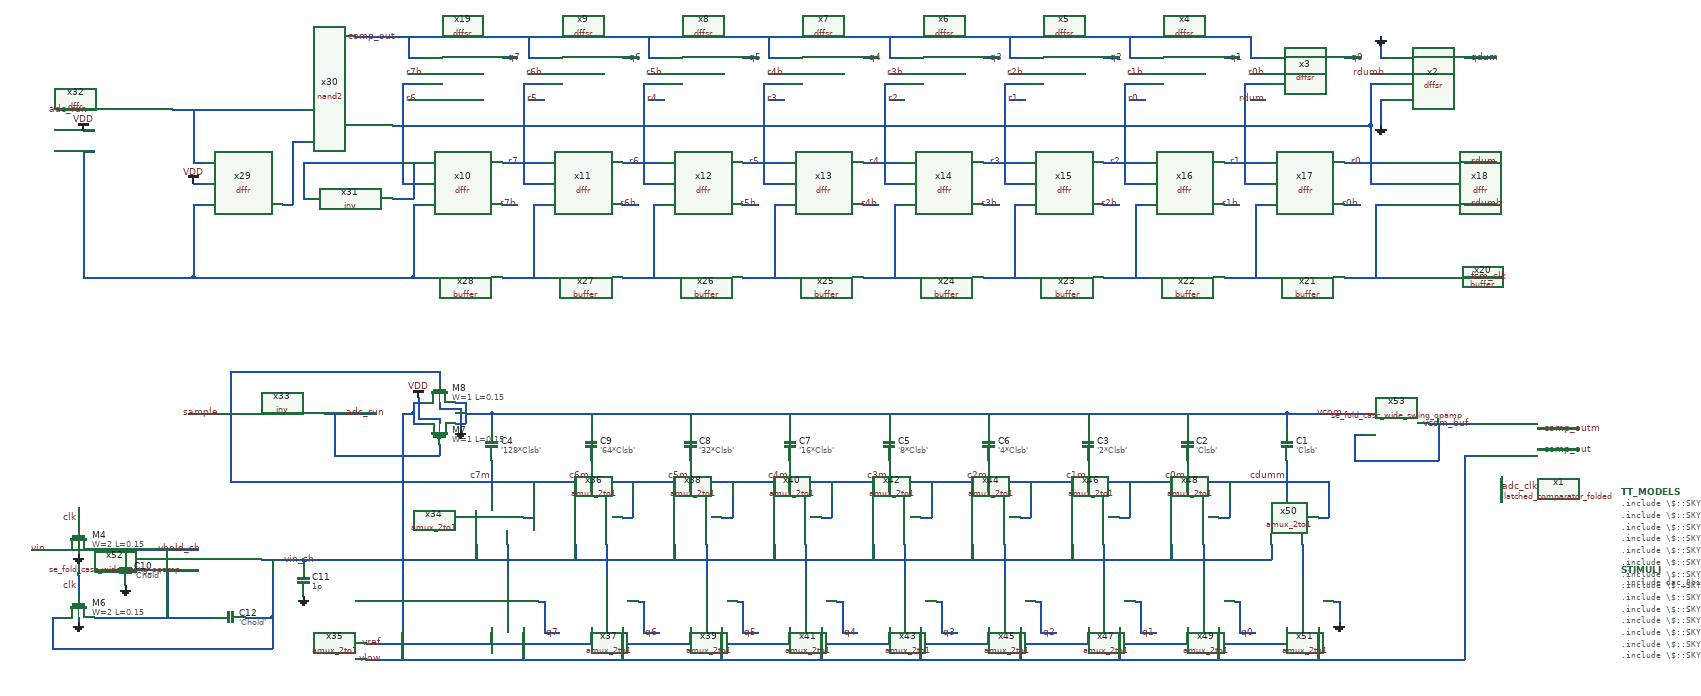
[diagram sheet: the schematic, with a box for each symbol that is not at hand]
v {xschem version=2.9.9 file_version=1.2 }
G {}
K {}
V {}
S {}
E {}
N 280 -1370 310 -1370 { lab=r6}
N 460 -1450 490 -1450 { lab=q7}
N 280 -1450 310 -1450 { lab=comp_out}
N 510 -1370 540 -1370 { lab=r5}
N 690 -1450 720 -1450 { lab=q6}
N 510 -1450 540 -1450 { lab=comp_out}
N 740 -1370 770 -1370 { lab=r4}
N 920 -1450 950 -1450 { lab=q5}
N 740 -1450 770 -1450 { lab=comp_out}
N 970 -1370 1000 -1370 { lab=r3}
N 1150 -1450 1180 -1450 { lab=q4}
N 970 -1450 1000 -1450 { lab=comp_out}
N 1200 -1370 1230 -1370 { lab=r2}
N 1380 -1450 1410 -1450 { lab=q3}
N 1200 -1450 1230 -1450 { lab=comp_out}
N 1430 -1370 1460 -1370 { lab=r1}
N 1610 -1450 1640 -1450 { lab=q2}
N 1430 -1450 1460 -1450 { lab=comp_out}
N 1660 -1370 1690 -1370 { lab=r0}
N 1840 -1450 1870 -1450 { lab=q1}
N 1660 -1450 1690 -1450 { lab=comp_out}
N 1890 -1370 1920 -1370 { lab=rdum}
N 2070 -1450 2100 -1450 { lab=q0}
N 1890 -1450 1920 -1450 { lab=comp_out}
N 180 -1490 1890 -1490 { lab=comp_out}
N 1890 -1490 1890 -1450 { lab=comp_out}
N 1660 -1490 1660 -1450 { lab=comp_out}
N 1430 -1490 1430 -1450 { lab=comp_out}
N 1200 -1490 1200 -1450 { lab=comp_out}
N 970 -1490 970 -1450 { lab=comp_out}
N 740 -1490 740 -1450 { lab=comp_out}
N 510 -1490 510 -1450 { lab=comp_out}
N 280 -1490 280 -1450 { lab=comp_out}
N 460 -1250 540 -1250 { lab=r7}
N 690 -1250 770 -1250 { lab=r6}
N 920 -1250 1000 -1250 { lab=r5}
N 1150 -1250 1230 -1250 { lab=r4}
N 1610 -1250 1690 -1250 { lab=r2}
N 1840 -1250 1920 -1250 { lab=r1}
N 2070 -1250 2150 -1250 { lab=r0}
N 1380 -1250 1460 -1250 { lab=r3}
N 460 -1170 490 -1170 { lab=r7b}
N 690 -1170 720 -1170 { lab=r6b}
N 920 -1170 950 -1170 { lab=r5b}
N 1150 -1170 1180 -1170 { lab=r4b}
N 1380 -1170 1410 -1170 { lab=r3b}
N 1610 -1170 1640 -1170 { lab=r2b}
N 1840 -1170 1870 -1170 { lab=r1b}
N 2070 -1170 2100 -1170 { lab=r0b}
N 280 -1420 310 -1420 { lab=r7b}
N 510 -1420 540 -1420 { lab=r6b}
N 740 -1420 770 -1420 { lab=r5b}
N 970 -1420 1000 -1420 { lab=r4b}
N 1200 -1420 1230 -1420 { lab=r3b}
N 1430 -1420 1460 -1420 { lab=r2b}
N 1660 -1420 1690 -1420 { lab=r1b}
N 1890 -1420 1920 -1420 { lab=r0b}
N 2120 -1420 2150 -1420 { lab=rdumb}
N 460 -1030 550 -1030 { lab=#net1}
N 690 -1030 780 -1030 { lab=#net2}
N 920 -1030 1010 -1030 { lab=#net3}
N 1150 -1030 1240 -1030 { lab=#net4}
N 1380 -1030 1470 -1030 { lab=#net5}
N 1610 -1030 1700 -1030 { lab=#net6}
N 1840 -1030 1930 -1030 { lab=#net7}
N 2070 -1030 2160 -1030 { lab=#net8}
N 2300 -1030 2370 -1030 { lab=fsm_clk}
N 290 -1030 320 -1030 { lab=#net9}
N 290 -1170 290 -1030 { lab=#net9}
N 520 -1170 540 -1170 { lab=#net1}
N 520 -1170 520 -1030 { lab=#net1}
N 750 -1170 770 -1170 { lab=#net2}
N 750 -1170 750 -1030 { lab=#net2}
N 980 -1170 1000 -1170 { lab=#net3}
N 980 -1170 980 -1030 { lab=#net3}
N 1210 -1170 1230 -1170 { lab=#net4}
N 1210 -1170 1210 -1030 { lab=#net4}
N 1440 -1170 1460 -1170 { lab=#net5}
N 1440 -1170 1440 -1030 { lab=#net5}
N 1670 -1170 1690 -1170 { lab=#net6}
N 1670 -1170 1670 -1030 { lab=#net6}
N 1900 -1170 1920 -1170 { lab=#net7}
N 1900 -1170 1900 -1030 { lab=#net7}
N 2130 -1170 2150 -1170 { lab=#net8}
N 2130 -1170 2130 -1030 { lab=#net8}
N 2120 -1400 2120 -1320 { lab=#net10}
N 2120 -1400 2150 -1400 { lab=#net10}
N 1880 -1400 1920 -1400 { lab=#net10}
N 1880 -1400 1880 -1320 { lab=#net10}
N 1650 -1400 1690 -1400 { lab=#net10}
N 1650 -1400 1650 -1320 { lab=#net10}
N 1420 -1400 1460 -1400 { lab=#net10}
N 1420 -1400 1420 -1320 { lab=#net10}
N 1190 -1400 1230 -1400 { lab=#net10}
N 1190 -1400 1190 -1320 { lab=#net10}
N 960 -1400 1000 -1400 { lab=#net10}
N 960 -1400 960 -1320 { lab=#net10}
N 730 -1400 770 -1400 { lab=#net10}
N 730 -1400 730 -1320 { lab=#net10}
N 500 -1400 540 -1400 { lab=#net10}
N 500 -1400 500 -1320 { lab=#net10}
N 270 -1400 310 -1400 { lab=#net10}
N 270 -1400 270 -1320 { lab=#net10}
N 290 -1170 310 -1170 { lab=#net9}
N 2300 -1170 2360 -1170 { lab=rdumb}
N 2300 -1250 2360 -1250 { lab=rdum}
N 2300 -1450 2360 -1450 { lab=qdum}
N 270 -1320 270 -1210 { lab=#net10}
N 270 -1210 310 -1210 { lab=#net10}
N 2140 -1370 2140 -1320 { lab=GND}
N 2140 -1450 2150 -1450 { lab=GND}
N 2140 -1490 2140 -1450 { lab=GND}
N 60 -1290 80 -1290 { lab=#net11}
N -130 -1250 -110 -1250 { lab=#net12}
N -130 -1350 -130 -1250 { lab=#net12}
N 250 -1320 2120 -1320 { lab=#net10}
N 60 -1290 60 -1170 { lab=#net11}
N 40 -1170 60 -1170 { lab=#net11}
N -130 -1030 290 -1030 { lab=#net9}
N -130 -1170 -130 -1030 { lab=#net9}
N -130 -1170 -110 -1170 { lab=#net9}
N 250 -1180 290 -1180 { lab=#net13}
N 290 -1250 290 -1180 { lab=#net13}
N 290 -1250 310 -1250 { lab=#net13}
N 80 -1180 90 -1180 { lab=#net10}
N 80 -1250 80 -1180 { lab=#net10}
N 80 -1250 270 -1250 { lab=#net10}
N -170 -1350 80 -1350 { lab=#net12}
N -340 -1270 -320 -1270 { lab=#net9}
N -340 -1270 -340 -1030 { lab=#net9}
N -340 -1030 -130 -1030 { lab=#net9}
N -340 -1310 -320 -1310 { lab=VDD}
N -130 -1210 -110 -1210 { lab=VDD}
N 510 -1370 540 -1370 { lab=r5}
N 740 -1370 770 -1370 { lab=r4}
N 970 -1370 1000 -1370 { lab=r3}
N 1200 -1370 1230 -1370 { lab=r2}
N 1430 -1370 1460 -1370 { lab=r1}
N 1660 -1370 1690 -1370 { lab=r0}
N 1890 -1370 1920 -1370 { lab=rdum}
N 500 -1320 500 -1210 { lab=#net10}
N 500 -1210 540 -1210 { lab=#net10}
N 730 -1320 730 -1210 { lab=#net10}
N 730 -1210 770 -1210 { lab=#net10}
N 960 -1320 960 -1210 { lab=#net10}
N 960 -1210 1000 -1210 { lab=#net10}
N 1190 -1320 1190 -1210 { lab=#net10}
N 1190 -1210 1230 -1210 { lab=#net10}
N 1420 -1320 1420 -1210 { lab=#net10}
N 1420 -1210 1460 -1210 { lab=#net10}
N 1650 -1320 1650 -1210 { lab=#net10}
N 1650 -1210 1690 -1210 { lab=#net10}
N 1880 -1320 1880 -1210 { lab=#net10}
N 1880 -1210 1920 -1210 { lab=#net10}
N 2120 -1320 2120 -1210 { lab=#net10}
N 2120 -1210 2160 -1210 { lab=#net10}
N -390 -1350 -320 -1350 { lab=adc_run}
N 2140 -1370 2150 -1370 { lab=GND}
N 0 -490 80 -490 { lab=vout2}
N -440 -510 -380 -510 { lab=vin}
N -350 -590 -350 -550 { lab=clk}
N -180 -470 -120 -470 { lab=#net4}
N -350 -510 -350 -500 { lab=GND}
N 80 -490 80 -480 { lab=vout2}
N -260 -510 -260 -500 { lab=vhold2}
N -320 -510 -120 -510 { lab=vhold2}
N -350 -460 -350 -420 { lab=clk}
N -350 -380 -350 -370 { lab=GND}
N -180 -470 -180 -380 { lab=#net4}
N -320 -380 -90 -380 { lab=#net4}
N 20 -490 20 -380 { lab=vout2}
N -30 -380 20 -380 { lab=vout2}
N -400 -380 -380 -380 { lab=vout2}
N -400 -380 -400 -320 { lab=vout2}
N -400 -320 20 -320 { lab=vout2}
N 20 -380 20 -320 { lab=vout2}
N 440 -770 440 -740 { lab=vcom}
N 440 -770 1960 -770 { lab=vcom}
N 1960 -770 1960 -740 { lab=vcom}
N 1770 -770 1770 -740 { lab=vcom}
N 1580 -770 1580 -740 { lab=vcom}
N 1390 -770 1390 -740 { lab=vcom}
N 1200 -770 1200 -740 { lab=vcom}
N 1010 -770 1010 -740 { lab=vcom}
N 820 -770 820 -740 { lab=vcom}
N 630 -770 630 -740 { lab=vcom}
N 1960 -770 2110 -770 { lab=vcom}
N 290 -790 290 -770 { lab=vlow}
N 290 -790 310 -790 { lab=vlow}
N 290 -770 290 -750 { lab=vlow}
N 290 -750 310 -750 { lab=vlow}
N 370 -790 390 -790 { lab=vcom}
N 390 -790 390 -750 { lab=vcom}
N 370 -750 390 -750 { lab=vcom}
N 340 -760 340 -750 { lab=VDD}
N 340 -790 340 -780 { lab=GND}
N 390 -770 440 -770 { lab=vcom}
N 340 -780 380 -780 { lab=GND}
N 380 -780 380 -740 { lab=GND}
N 300 -800 300 -760 { lab=VDD}
N 300 -760 340 -760 { lab=VDD}
N 270 -770 290 -770 { lab=vlow}
N 2440 -700 2520 -700 { lab=comp_out}
N -140 -770 -40 -770 { lab=sample}
N 120 -770 220 -770 { lab=adc_run}
N -60 -770 -60 -640 { lab=sample}
N -60 -640 2040 -640 { lab=sample}
N 470 -520 470 -460 { lab=#net1}
N 660 -520 660 -460 { lab=#net2}
N 850 -520 850 -460 { lab=#net3}
N 1040 -520 1040 -460 { lab=#net4}
N 1230 -520 1230 -460 { lab=#net5}
N 1420 -520 1420 -460 { lab=#net6}
N 1610 -520 1610 -460 { lab=#net7}
N 1800 -520 1800 -460 { lab=#net8}
N 1990 -520 1990 -460 { lab=#net9}
N 200 -490 1930 -490 { lab=vin}
N 1930 -520 1930 -490 { lab=vin}
N 410 -520 410 -490 { lab=vin}
N 600 -520 600 -490 { lab=vin}
N 790 -520 790 -490 { lab=vin}
N 980 -520 980 -490 { lab=vin}
N 1170 -520 1170 -490 { lab=vin}
N 1360 -520 1360 -490 { lab=vin}
N 1550 -520 1550 -490 { lab=vin}
N 1740 -520 1740 -490 { lab=vin}
N 1960 -360 1960 -330 { lab=vref}
N 440 -360 440 -330 { lab=vref}
N 630 -360 630 -330 { lab=vref}
N 820 -360 820 -330 { lab=vref}
N 1010 -360 1010 -330 { lab=vref}
N 1200 -360 1200 -330 { lab=vref}
N 1390 -360 1390 -330 { lab=vref}
N 1580 -360 1580 -330 { lab=vref}
N 1770 -360 1770 -330 { lab=vref}
N 200 -330 1960 -330 { lab=vref}
N 2020 -360 2020 -300 { lab=vlow}
N 1830 -360 1830 -300 { lab=vlow}
N 1640 -360 1640 -300 { lab=vlow}
N 1450 -360 1450 -300 { lab=vlow}
N 1260 -360 1260 -300 { lab=vlow}
N 1070 -360 1070 -300 { lab=vlow}
N 880 -360 880 -300 { lab=vlow}
N 690 -360 690 -300 { lab=vlow}
N 500 -360 500 -300 { lab=vlow}
N 270 -770 270 -300 { lab=vlow}
N 440 -680 440 -620 { lab=c7m}
N 630 -680 630 -620 { lab=c6m}
N 820 -680 820 -620 { lab=c5m}
N 1010 -680 1010 -620 { lab=c4m}
N 1200 -680 1200 -620 { lab=c3m}
N 1390 -680 1390 -620 { lab=c2m}
N 1580 -680 1580 -620 { lab=c1m}
N 1770 -680 1770 -620 { lab=c0m}
N 1960 -680 1960 -620 { lab=cdumm}
N 500 -570 520 -570 { lab=sample}
N 520 -640 520 -570 { lab=sample}
N 690 -570 710 -570 { lab=sample}
N 710 -640 710 -570 { lab=sample}
N 880 -570 900 -570 { lab=sample}
N 900 -640 900 -570 { lab=sample}
N 1070 -570 1090 -570 { lab=sample}
N 1090 -640 1090 -570 { lab=sample}
N 1260 -570 1280 -570 { lab=sample}
N 1280 -640 1280 -570 { lab=sample}
N 1450 -570 1470 -570 { lab=sample}
N 1470 -640 1470 -570 { lab=sample}
N 1640 -570 1660 -570 { lab=sample}
N 1660 -640 1660 -570 { lab=sample}
N 1830 -570 1850 -570 { lab=sample}
N 1850 -640 1850 -570 { lab=sample}
N 2020 -570 2040 -570 { lab=sample}
N 2040 -640 2040 -570 { lab=sample}
N 540 -350 570 -350 { lab=q7}
N 730 -350 760 -350 { lab=q6}
N 920 -350 950 -350 { lab=q5}
N 1110 -350 1140 -350 { lab=q4}
N 1300 -350 1330 -350 { lab=q3}
N 1490 -350 1520 -350 { lab=q2}
N 1680 -350 1710 -350 { lab=q1}
N 1870 -350 1900 -350 { lab=q0}
N 530 -410 540 -410 { lab=q7}
N 540 -410 540 -350 { lab=q7}
N 720 -410 730 -410 { lab=q6}
N 730 -410 730 -350 { lab=q6}
N 910 -410 920 -410 { lab=q5}
N 920 -410 920 -350 { lab=q5}
N 1100 -410 1110 -410 { lab=q4}
N 1110 -410 1110 -350 { lab=q4}
N 1290 -410 1300 -410 { lab=q3}
N 1300 -410 1300 -350 { lab=q3}
N 1480 -410 1490 -410 { lab=q2}
N 1490 -410 1490 -350 { lab=q2}
N 1670 -410 1680 -410 { lab=q1}
N 1680 -410 1680 -350 { lab=q1}
N 1860 -410 1870 -410 { lab=q0}
N 1870 -410 1870 -350 { lab=q0}
N -60 -850 -60 -770 { lab=sample}
N -60 -850 340 -850 { lab=sample}
N 340 -850 340 -830 { lab=sample}
N 140 -770 140 -690 { lab=adc_run}
N 140 -690 340 -690 { lab=adc_run}
N 340 -710 340 -690 { lab=adc_run}
N 2050 -410 2060 -410 { lab=GND}
N 2060 -410 2060 -370 { lab=GND}
N 2300 -690 2320 -690 { lab=vlow}
N 2370 -650 2370 -600 { lab=adc_clk}
N 2440 -740 2520 -740 { lab=comp_outm}
N 2090 -730 2110 -730 { lab=vcom_buf}
N 2090 -730 2090 -680 { lab=vcom_buf}
N 2230 -750 2320 -750 { lab=vcom_buf}
N 2090 -680 2250 -680 { lab=vcom_buf}
N 2250 -750 2250 -680 { lab=vcom_buf}
N 2300 -690 2300 -300 { lab=vlow}
N 200 -300 2300 -300 { lab=vlow}
N 80 -490 200 -490 {}
C {devices/title.sym} 160 -30 0 0 {name=l1 author="Nikhil Poole"}
C {devices/code.sym} 2600 -470 0 0 {name=STIMULI 
only_toplevel=true
place=end
value=".include dac_8bit_commands.spice"}
C {devices/code.sym} 2600 -620 0 0 {name=TT_MODELS
only_toplevel=true
format="tcleval( @value )"
value="
.include \\\\$::SKYWATER_MODELS\\\\/cells/nfet_01v8/sky130_fd_pr__nfet_01v8__tt.corner.spice
.include \\\\$::SKYWATER_MODELS\\\\/cells/nfet_01v8_lvt/sky130_fd_pr__nfet_01v8_lvt__tt.corner.spice
.include \\\\$::SKYWATER_MODELS\\\\/cells/pfet_01v8/sky130_fd_pr__pfet_01v8__tt.corner.spice
.include \\\\$::SKYWATER_MODELS\\\\/cells/nfet_03v3_nvt/sky130_fd_pr__nfet_03v3_nvt__tt.corner.spice
.include \\\\$::SKYWATER_MODELS\\\\/cells/nfet_05v0_nvt/sky130_fd_pr__nfet_05v0_nvt__tt.corner.spice
.include \\\\$::SKYWATER_MODELS\\\\/cells/esd_nfet_01v8/sky130_fd_pr__esd_nfet_01v8__tt.corner.spice
.include \\\\$::SKYWATER_MODELS\\\\/cells/pfet_01v8_lvt/sky130_fd_pr__pfet_01v8_lvt__tt.corner.spice
.include \\\\$::SKYWATER_MODELS\\\\/cells/pfet_01v8_hvt/sky130_fd_pr__pfet_01v8_hvt__tt.corner.spice
.include \\\\$::SKYWATER_MODELS\\\\/cells/esd_pfet_g5v0d10v5/sky130_fd_pr__esd_pfet_g5v0d10v5__tt.corner.spice
.include \\\\$::SKYWATER_MODELS\\\\/cells/pfet_g5v0d10v5/sky130_fd_pr__pfet_g5v0d10v5__tt.corner.spice
.include \\\\$::SKYWATER_MODELS\\\\/cells/pfet_g5v0d16v0/sky130_fd_pr__pfet_g5v0d16v0__tt.corner.spice
.include \\\\$::SKYWATER_MODELS\\\\/cells/nfet_g5v0d10v5/sky130_fd_pr__nfet_g5v0d10v5__tt.corner.spice
.include \\\\$::SKYWATER_MODELS\\\\/cells/nfet_g5v0d16v0/sky130_fd_pr__nfet_g5v0d16v0__tt_discrete.corner.spice
.include \\\\$::SKYWATER_MODELS\\\\/cells/esd_nfet_g5v0d10v5/sky130_fd_pr__esd_nfet_g5v0d10v5__tt.corner.spice
.include \\\\$::SKYWATER_MODELS\\\\/models/corners/tt/nonfet.spice
* Mismatch parameters
.include \\\\$::SKYWATER_MODELS\\\\/cells/nfet_01v8/sky130_fd_pr__nfet_01v8__mismatch.corner.spice
.include \\\\$::SKYWATER_MODELS\\\\/cells/pfet_01v8/sky130_fd_pr__pfet_01v8__mismatch.corner.spice
.include \\\\$::SKYWATER_MODELS\\\\/cells/nfet_01v8_lvt/sky130_fd_pr__nfet_01v8_lvt__mismatch.corner.spice
.include \\\\$::SKYWATER_MODELS\\\\/cells/pfet_01v8_lvt/sky130_fd_pr__pfet_01v8_lvt__mismatch.corner.spice
.include \\\\$::SKYWATER_MODELS\\\\/cells/pfet_01v8_hvt/sky130_fd_pr__pfet_01v8_hvt__mismatch.corner.spice
.include \\\\$::SKYWATER_MODELS\\\\/cells/nfet_g5v0d10v5/sky130_fd_pr__nfet_g5v0d10v5__mismatch.corner.spice
.include \\\\$::SKYWATER_MODELS\\\\/cells/pfet_g5v0d10v5/sky130_fd_pr__pfet_g5v0d10v5__mismatch.corner.spice
.include \\\\$::SKYWATER_MODELS\\\\/cells/nfet_05v0_nvt/sky130_fd_pr__nfet_05v0_nvt__mismatch.corner.spice
.include \\\\$::SKYWATER_MODELS\\\\/cells/nfet_03v3_nvt/sky130_fd_pr__nfet_03v3_nvt__mismatch.corner.spice
* Resistor\\\\$::SKYWATER_MODELS\\\\/Capacitor
.include \\\\$::SKYWATER_MODELS\\\\/models/r+c/res_typical__cap_typical.spice
.include \\\\$::SKYWATER_MODELS\\\\/models/r+c/res_typical__cap_typical__lin.spice
* Special cells
.include \\\\$::SKYWATER_MODELS\\\\/models/corners/tt/specialized_cells.spice
* All models
.include \\\\$::SKYWATER_MODELS\\\\/models/all.spice
* Corner
.include \\\\$::SKYWATER_MODELS\\\\/models/corners/tt/rf.spice
"}
C {devices/lab_wire.sym} 260 -1490 0 0 {name=l3 sig_type=std_logic lab=comp_out}
C {devices/lab_wire.sym} 300 -1370 0 0 {name=l4 sig_type=std_logic lab=r6}
C {devices/lab_wire.sym} 470 -1450 0 1 {name=l6 sig_type=std_logic lab=q7}
C {devices/lab_wire.sym} 530 -1370 0 0 {name=l9 sig_type=std_logic lab=r5}
C {devices/lab_wire.sym} 700 -1450 0 1 {name=l11 sig_type=std_logic lab=q6}
C {devices/lab_wire.sym} 760 -1370 0 0 {name=l14 sig_type=std_logic lab=r4}
C {devices/lab_wire.sym} 930 -1450 0 1 {name=l15 sig_type=std_logic lab=q5}
C {devices/lab_wire.sym} 990 -1370 0 0 {name=l17 sig_type=std_logic lab=r3}
C {devices/lab_wire.sym} 1160 -1450 0 1 {name=l18 sig_type=std_logic lab=q4}
C {devices/lab_wire.sym} 1220 -1370 0 0 {name=l20 sig_type=std_logic lab=r2}
C {devices/lab_wire.sym} 1390 -1450 0 1 {name=l21 sig_type=std_logic lab=q3}
C {devices/lab_wire.sym} 1450 -1370 0 0 {name=l23 sig_type=std_logic lab=r1}
C {devices/lab_wire.sym} 1620 -1450 0 1 {name=l24 sig_type=std_logic lab=q2}
C {devices/lab_wire.sym} 1680 -1370 0 0 {name=l27 sig_type=std_logic lab=r0}
C {devices/lab_wire.sym} 1850 -1450 0 1 {name=l28 sig_type=std_logic lab=q1}
C {devices/lab_wire.sym} 1920 -1370 0 0 {name=l30 sig_type=std_logic lab=rdum}
C {devices/lab_wire.sym} 2080 -1450 0 1 {name=l31 sig_type=std_logic lab=q0}
C {devices/lab_wire.sym} 2310 -1450 0 1 {name=l33 sig_type=std_logic lab=qdum}
C {/home/users/nhpoole/ee272b/ee272b_mixed_signal_mmwave_accelerator/designs/dffr.sym} 380 -1210 0 0 {name=x10 M=1}
C {/home/users/nhpoole/ee272b/ee272b_mixed_signal_mmwave_accelerator/designs/dffr.sym} 610 -1210 0 0 {name=x11 M=1}
C {/home/users/nhpoole/ee272b/ee272b_mixed_signal_mmwave_accelerator/designs/dffr.sym} 840 -1210 0 0 {name=x12 M=1}
C {/home/users/nhpoole/ee272b/ee272b_mixed_signal_mmwave_accelerator/designs/dffr.sym} 1070 -1210 0 0 {name=x13 M=1}
C {/home/users/nhpoole/ee272b/ee272b_mixed_signal_mmwave_accelerator/designs/dffr.sym} 1300 -1210 0 0 {name=x14 M=1}
C {/home/users/nhpoole/ee272b/ee272b_mixed_signal_mmwave_accelerator/designs/dffr.sym} 1530 -1210 0 0 {name=x15 M=1}
C {/home/users/nhpoole/ee272b/ee272b_mixed_signal_mmwave_accelerator/designs/dffr.sym} 1760 -1210 0 0 {name=x16 M=1}
C {/home/users/nhpoole/ee272b/ee272b_mixed_signal_mmwave_accelerator/designs/dffr.sym} 1990 -1210 0 0 {name=x17 M=1}
C {devices/lab_wire.sym} 470 -1250 0 1 {name=l34 sig_type=std_logic lab=r7}
C {devices/lab_wire.sym} 700 -1250 0 1 {name=l87 sig_type=std_logic lab=r6}
C {devices/lab_wire.sym} 930 -1250 0 1 {name=l88 sig_type=std_logic lab=r5}
C {devices/lab_wire.sym} 1160 -1250 0 1 {name=l89 sig_type=std_logic lab=r4}
C {devices/lab_wire.sym} 1620 -1250 0 1 {name=l90 sig_type=std_logic lab=r2}
C {devices/lab_wire.sym} 1850 -1250 0 1 {name=l91 sig_type=std_logic lab=r1}
C {devices/lab_wire.sym} 2080 -1250 0 1 {name=l92 sig_type=std_logic lab=r0}
C {devices/lab_wire.sym} 1390 -1250 0 1 {name=l93 sig_type=std_logic lab=r3}
C {/home/users/nhpoole/ee272b/ee272b_mixed_signal_mmwave_accelerator/designs/dffr.sym} 2220 -1210 0 0 {name=x18 M=1}
C {devices/lab_wire.sym} 2310 -1250 0 1 {name=l94 sig_type=std_logic lab=rdum}
C {/home/users/nhpoole/ee272b/ee272b_mixed_signal_mmwave_accelerator/designs/dffsr.sym} 2220 -1410 0 0 {name=x2 M=1}
C {/home/users/nhpoole/ee272b/ee272b_mixed_signal_mmwave_accelerator/designs/dffsr.sym} 1990 -1410 0 0 {name=x3 M=1}
C {/home/users/nhpoole/ee272b/ee272b_mixed_signal_mmwave_accelerator/designs/dffsr.sym} 1760 -1410 0 0 {name=x4 M=1}
C {/home/users/nhpoole/ee272b/ee272b_mixed_signal_mmwave_accelerator/designs/dffsr.sym} 1530 -1410 0 0 {name=x5 M=1}
C {/home/users/nhpoole/ee272b/ee272b_mixed_signal_mmwave_accelerator/designs/dffsr.sym} 1300 -1410 0 0 {name=x6 M=1}
C {/home/users/nhpoole/ee272b/ee272b_mixed_signal_mmwave_accelerator/designs/dffsr.sym} 1070 -1410 0 0 {name=x7 M=1}
C {/home/users/nhpoole/ee272b/ee272b_mixed_signal_mmwave_accelerator/designs/dffsr.sym} 840 -1410 0 0 {name=x8 M=1}
C {/home/users/nhpoole/ee272b/ee272b_mixed_signal_mmwave_accelerator/designs/dffsr.sym} 610 -1410 0 0 {name=x9 M=1}
C {/home/users/nhpoole/ee272b/ee272b_mixed_signal_mmwave_accelerator/designs/dffsr.sym} 380 -1410 0 0 {name=x19 M=1}
C {devices/lab_wire.sym} 490 -1170 0 0 {name=l95 sig_type=std_logic lab=r7b}
C {devices/lab_wire.sym} 720 -1170 0 0 {name=l96 sig_type=std_logic lab=r6b}
C {devices/lab_wire.sym} 950 -1170 0 0 {name=l97 sig_type=std_logic lab=r5b}
C {devices/lab_wire.sym} 1180 -1170 0 0 {name=l98 sig_type=std_logic lab=r4b}
C {devices/lab_wire.sym} 1410 -1170 0 0 {name=l99 sig_type=std_logic lab=r3b}
C {devices/lab_wire.sym} 1640 -1170 0 0 {name=l100 sig_type=std_logic lab=r2b}
C {devices/lab_wire.sym} 1870 -1170 0 0 {name=l101 sig_type=std_logic lab=r1b}
C {devices/lab_wire.sym} 2100 -1170 0 0 {name=l102 sig_type=std_logic lab=r0b}
C {devices/lab_wire.sym} 2310 -1170 0 1 {name=l103 sig_type=std_logic lab=rdumb}
C {devices/lab_wire.sym} 310 -1420 0 0 {name=l104 sig_type=std_logic lab=r7b}
C {devices/lab_wire.sym} 540 -1420 0 0 {name=l105 sig_type=std_logic lab=r6b}
C {devices/lab_wire.sym} 770 -1420 0 0 {name=l106 sig_type=std_logic lab=r5b}
C {devices/lab_wire.sym} 1000 -1420 0 0 {name=l107 sig_type=std_logic lab=r4b}
C {devices/lab_wire.sym} 1230 -1420 0 0 {name=l108 sig_type=std_logic lab=r3b}
C {devices/lab_wire.sym} 1460 -1420 0 0 {name=l109 sig_type=std_logic lab=r2b}
C {devices/lab_wire.sym} 1690 -1420 0 0 {name=l110 sig_type=std_logic lab=r1b}
C {devices/lab_wire.sym} 1920 -1420 0 0 {name=l111 sig_type=std_logic lab=r0b}
C {devices/lab_wire.sym} 2150 -1420 0 0 {name=l112 sig_type=std_logic lab=rdumb}
C {/home/users/nhpoole/ee272b/ee272b_mixed_signal_mmwave_accelerator/designs/buffer.sym} 2250 -1030 0 1 {name=x20 M=1}
C {/home/users/nhpoole/ee272b/ee272b_mixed_signal_mmwave_accelerator/designs/buffer.sym} 2020 -1030 0 1 {name=x21 M=1}
C {/home/users/nhpoole/ee272b/ee272b_mixed_signal_mmwave_accelerator/designs/buffer.sym} 1790 -1030 0 1 {name=x22 M=1}
C {/home/users/nhpoole/ee272b/ee272b_mixed_signal_mmwave_accelerator/designs/buffer.sym} 1560 -1030 0 1 {name=x23 M=1}
C {/home/users/nhpoole/ee272b/ee272b_mixed_signal_mmwave_accelerator/designs/buffer.sym} 1330 -1030 0 1 {name=x24 M=1}
C {/home/users/nhpoole/ee272b/ee272b_mixed_signal_mmwave_accelerator/designs/buffer.sym} 1100 -1030 0 1 {name=x25 M=1}
C {/home/users/nhpoole/ee272b/ee272b_mixed_signal_mmwave_accelerator/designs/buffer.sym} 870 -1030 0 1 {name=x26 M=1}
C {/home/users/nhpoole/ee272b/ee272b_mixed_signal_mmwave_accelerator/designs/buffer.sym} 640 -1030 0 1 {name=x27 M=1}
C {/home/users/nhpoole/ee272b/ee272b_mixed_signal_mmwave_accelerator/designs/buffer.sym} 410 -1030 0 1 {name=x28 M=1}
C {devices/lab_wire.sym} 2310 -1030 0 1 {name=l113 sig_type=std_logic lab=fsm_clk}
C {devices/gnd.sym} 2140 -1320 0 0 {name=l114 lab=GND}
C {devices/gnd.sym} 2140 -1490 2 1 {name=l115 lab=GND}
C {/home/users/nhpoole/ee272b/ee272b_mixed_signal_mmwave_accelerator/designs/dffr.sym} -40 -1210 0 0 {name=x29 M=1}
C {devices/noconn.sym} 40 -1250 0 1 {name=l116}
C {/home/users/nhpoole/ee272b/ee272b_mixed_signal_mmwave_accelerator/designs/nand2.sym} 150 -1320 0 0 {name=x30 M=1}
C {/home/users/nhpoole/ee272b/ee272b_mixed_signal_mmwave_accelerator/designs/inv.sym} 140 -1180 0 0 {name=x31 M=1}
C {/home/users/nhpoole/ee272b/ee272b_mixed_signal_mmwave_accelerator/designs/dffr.sym} -250 -1310 0 0 {name=x32 M=1}
C {devices/lab_wire.sym} -330 -1350 0 0 {name=l117 sig_type=std_logic lab=adc_run}
C {devices/noconn.sym} -170 -1270 0 1 {name=l118}
C {devices/vdd.sym} -340 -1310 0 0 {name=l119 lab=VDD}
C {devices/vdd.sym} -130 -1210 0 0 {name=l120 lab=VDD}
C {devices/noconn.sym} 460 -1370 0 1 {name=l64}
C {devices/noconn.sym} 690 -1370 0 1 {name=l65}
C {devices/noconn.sym} 920 -1370 0 1 {name=l66}
C {devices/noconn.sym} 1150 -1370 0 1 {name=l67}
C {devices/noconn.sym} 1380 -1370 0 1 {name=l68}
C {devices/noconn.sym} 1610 -1370 0 1 {name=l69}
C {devices/noconn.sym} 1840 -1370 0 1 {name=l70}
C {devices/noconn.sym} 2070 -1370 0 1 {name=l71}
C {devices/noconn.sym} 2300 -1370 0 1 {name=l72}
C {sky130_fd_pr/nfet_01v8.sym} -350 -530 1 0 {name=M4
L=0.15
W=2
nf=1 
mult=1
ad="'int((nf+1)/2) * W/nf * 0.29'" 
pd="'2*int((nf+1)/2) * (W/nf + 0.29)'"
as="'int((nf+2)/2) * W/nf * 0.29'" 
ps="'2*int((nf+2)/2) * (W/nf + 0.29)'"
nrd="'0.29 / W'" nrs="'0.29 / W'"
sa=0 sb=0 sd=0
model=nfet_01v8
spiceprefix=X
}
C {/home/users/nhpoole/ee272b/ee272b_mixed_signal_mmwave_accelerator/designs/se_fold_casc_wide_swing_opamp.sym} -70 -490 0 0 {name=x52}
C {devices/capa.sym} -260 -470 0 0 {name=C10
m=1
value='Chold'
footprint=1206
device="ceramic capacitor"}
C {devices/lab_wire.sym} 40 -490 0 1 {name=l29 sig_type=std_logic lab=vin_sh}
C {devices/lab_wire.sym} -410 -510 0 0 {name=l32 sig_type=std_logic lab=vin}
C {devices/lab_wire.sym} -350 -570 0 0 {name=l35 sig_type=std_logic lab=clk}
C {devices/lab_wire.sym} -200 -510 0 1 {name=l36 sig_type=std_logic lab=vhold_sh}
C {devices/gnd.sym} -350 -500 0 1 {name=l37 lab=GND}
C {devices/capa.sym} 80 -450 0 0 {name=C11
m=1
value=1p
footprint=1206
device="ceramic capacitor"}
C {devices/gnd.sym} 80 -420 0 1 {name=l38 lab=GND}
C {sky130_fd_pr/nfet_01v8.sym} -350 -400 1 0 {name=M6
L=0.15
W=2
nf=1 
mult=1
ad="'int((nf+1)/2) * W/nf * 0.29'" 
pd="'2*int((nf+1)/2) * (W/nf + 0.29)'"
as="'int((nf+2)/2) * W/nf * 0.29'" 
ps="'2*int((nf+2)/2) * (W/nf + 0.29)'"
nrd="'0.29 / W'" nrs="'0.29 / W'"
sa=0 sb=0 sd=0
model=nfet_01v8
spiceprefix=X
}
C {devices/lab_wire.sym} -350 -440 0 0 {name=l49 sig_type=std_logic lab=clk}
C {devices/gnd.sym} -350 -370 0 1 {name=l50 lab=GND}
C {devices/capa.sym} -60 -380 3 0 {name=C12
m=1
value='Chold'
footprint=1206
device="ceramic capacitor"}
C {devices/gnd.sym} -260 -440 0 1 {name=l51 lab=GND}
C {devices/capa.sym} 1960 -710 0 0 {name=C1
m=1
value='Clsb'
footprint=1206
device="ceramic capacitor"}
C {devices/capa.sym} 1770 -710 0 0 {name=C2
m=1
value='Clsb'
footprint=1206
device="ceramic capacitor"}
C {devices/capa.sym} 1580 -710 0 0 {name=C3
m=1
value='2*Clsb'
footprint=1206
device="ceramic capacitor"}
C {devices/capa.sym} 440 -710 0 0 {name=C4
m=1
value='128*Clsb'
footprint=1206
device="ceramic capacitor"}
C {devices/capa.sym} 1200 -710 0 0 {name=C5
m=1
value='8*Clsb'
footprint=1206
device="ceramic capacitor"}
C {devices/capa.sym} 1390 -710 0 0 {name=C6
m=1
value='4*Clsb'
footprint=1206
device="ceramic capacitor"}
C {devices/capa.sym} 1010 -710 0 0 {name=C7
m=1
value='16*Clsb'
footprint=1206
device="ceramic capacitor"}
C {devices/capa.sym} 820 -710 0 0 {name=C8
m=1
value='32*Clsb'
footprint=1206
device="ceramic capacitor"}
C {devices/capa.sym} 630 -710 0 0 {name=C9
m=1
value='64*Clsb'
footprint=1206
device="ceramic capacitor"}
C {sky130_fd_pr/pfet_01v8_hvt.sym} 340 -730 3 0 {name=M7
L=0.15
W=1
nf=1
mult=1
ad="'int((nf+1)/2) * W/nf * 0.29'" 
pd="'2*int((nf+1)/2) * (W/nf + 0.29)'"
as="'int((nf+2)/2) * W/nf * 0.29'" 
ps="'2*int((nf+2)/2) * (W/nf + 0.29)'"
nrd="'0.29 / W'" nrs="'0.29 / W'"
sa=0 sb=0 sd=0
model=pfet_01v8_hvt
spiceprefix=X
}
C {sky130_fd_pr/nfet_01v8.sym} 340 -810 3 1 {name=M8
L=0.15
W=1
nf=1 
mult=1
ad="'int((nf+1)/2) * W/nf * 0.29'" 
pd="'2*int((nf+1)/2) * (W/nf + 0.29)'"
as="'int((nf+2)/2) * W/nf * 0.29'" 
ps="'2*int((nf+2)/2) * (W/nf + 0.29)'"
nrd="'0.29 / W'" nrs="'0.29 / W'"
sa=0 sb=0 sd=0
model=nfet_01v8
spiceprefix=X
}
C {devices/vdd.sym} 300 -800 0 0 {name=l121 lab=VDD}
C {devices/gnd.sym} 380 -740 0 0 {name=l122 lab=GND}
C {/home/users/nhpoole/ee272b/ee272b_mixed_signal_mmwave_accelerator/designs/inv.sym} 10 -770 0 0 {name=x33 M=1}
C {devices/lab_wire.sym} 160 -770 0 1 {name=l123 sig_type=std_logic lab=adc_run}
C {devices/lab_wire.sym} 2450 -700 0 1 {name=l124 sig_type=std_logic lab=comp_out}
C {devices/lab_wire.sym} -80 -770 0 0 {name=l125 sig_type=std_logic lab=sample}
C {/home/users/nhpoole/ee272b/ee272b_mixed_signal_mmwave_accelerator/designs/amux_2to1.sym} 440 -570 3 0 {name=x34 M=1}
C {/home/users/nhpoole/ee272b/ee272b_mixed_signal_mmwave_accelerator/designs/amux_2to1.sym} 470 -410 3 0 {name=x35 M=1}
C {/home/users/nhpoole/ee272b/ee272b_mixed_signal_mmwave_accelerator/designs/amux_2to1.sym} 630 -570 3 0 {name=x36 M=1}
C {/home/users/nhpoole/ee272b/ee272b_mixed_signal_mmwave_accelerator/designs/amux_2to1.sym} 660 -410 3 0 {name=x37 M=1}
C {/home/users/nhpoole/ee272b/ee272b_mixed_signal_mmwave_accelerator/designs/amux_2to1.sym} 820 -570 3 0 {name=x38 M=1}
C {/home/users/nhpoole/ee272b/ee272b_mixed_signal_mmwave_accelerator/designs/amux_2to1.sym} 850 -410 3 0 {name=x39 M=1}
C {/home/users/nhpoole/ee272b/ee272b_mixed_signal_mmwave_accelerator/designs/amux_2to1.sym} 1010 -570 3 0 {name=x40 M=1}
C {/home/users/nhpoole/ee272b/ee272b_mixed_signal_mmwave_accelerator/designs/amux_2to1.sym} 1040 -410 3 0 {name=x41 M=1}
C {/home/users/nhpoole/ee272b/ee272b_mixed_signal_mmwave_accelerator/designs/amux_2to1.sym} 1200 -570 3 0 {name=x42 M=1}
C {/home/users/nhpoole/ee272b/ee272b_mixed_signal_mmwave_accelerator/designs/amux_2to1.sym} 1230 -410 3 0 {name=x43 M=1}
C {/home/users/nhpoole/ee272b/ee272b_mixed_signal_mmwave_accelerator/designs/amux_2to1.sym} 1390 -570 3 0 {name=x44 M=1}
C {/home/users/nhpoole/ee272b/ee272b_mixed_signal_mmwave_accelerator/designs/amux_2to1.sym} 1420 -410 3 0 {name=x45 M=1}
C {/home/users/nhpoole/ee272b/ee272b_mixed_signal_mmwave_accelerator/designs/amux_2to1.sym} 1580 -570 3 0 {name=x46 M=1}
C {/home/users/nhpoole/ee272b/ee272b_mixed_signal_mmwave_accelerator/designs/amux_2to1.sym} 1610 -410 3 0 {name=x47 M=1}
C {/home/users/nhpoole/ee272b/ee272b_mixed_signal_mmwave_accelerator/designs/amux_2to1.sym} 1770 -570 3 0 {name=x48 M=1}
C {/home/users/nhpoole/ee272b/ee272b_mixed_signal_mmwave_accelerator/designs/amux_2to1.sym} 1800 -410 3 0 {name=x49 M=1}
C {/home/users/nhpoole/ee272b/ee272b_mixed_signal_mmwave_accelerator/designs/amux_2to1.sym} 1960 -570 3 0 {name=x50 M=1}
C {/home/users/nhpoole/ee272b/ee272b_mixed_signal_mmwave_accelerator/designs/amux_2to1.sym} 1990 -410 3 0 {name=x51 M=1}
C {devices/lab_wire.sym} 230 -330 0 0 {name=l39 sig_type=std_logic lab=vref}
C {devices/lab_wire.sym} 230 -300 0 0 {name=l40 sig_type=std_logic lab=vlow}
C {devices/lab_wire.sym} 570 -350 0 0 {name=l41 sig_type=std_logic lab=q7}
C {devices/lab_wire.sym} 760 -350 0 0 {name=l42 sig_type=std_logic lab=q6}
C {devices/lab_wire.sym} 950 -350 0 0 {name=l43 sig_type=std_logic lab=q5}
C {devices/lab_wire.sym} 1140 -350 0 0 {name=l44 sig_type=std_logic lab=q4}
C {devices/lab_wire.sym} 1330 -350 0 0 {name=l45 sig_type=std_logic lab=q3}
C {devices/lab_wire.sym} 1520 -350 0 0 {name=l46 sig_type=std_logic lab=q2}
C {devices/lab_wire.sym} 1710 -350 0 0 {name=l47 sig_type=std_logic lab=q1}
C {devices/lab_wire.sym} 1900 -350 0 0 {name=l48 sig_type=std_logic lab=q0}
C {devices/gnd.sym} 2060 -370 0 1 {name=l2 lab=GND}
C {devices/lab_wire.sym} 440 -650 0 0 {name=l5 sig_type=std_logic lab=c7m}
C {devices/lab_wire.sym} 630 -650 0 0 {name=l8 sig_type=std_logic lab=c6m}
C {devices/lab_wire.sym} 820 -650 0 0 {name=l10 sig_type=std_logic lab=c5m}
C {devices/lab_wire.sym} 1010 -650 0 0 {name=l12 sig_type=std_logic lab=c4m}
C {devices/lab_wire.sym} 1200 -650 0 0 {name=l13 sig_type=std_logic lab=c3m}
C {devices/lab_wire.sym} 1390 -650 0 0 {name=l16 sig_type=std_logic lab=c2m}
C {devices/lab_wire.sym} 1580 -650 0 0 {name=l19 sig_type=std_logic lab=c1m}
C {devices/lab_wire.sym} 1770 -650 0 0 {name=l22 sig_type=std_logic lab=c0m}
C {devices/lab_wire.sym} 1960 -650 0 0 {name=l25 sig_type=std_logic lab=cdumm}
C {devices/lab_wire.sym} 2070 -770 0 0 {name=l26 sig_type=std_logic lab=vcom}
C {devices/lab_wire.sym} 2370 -630 2 0 {name=l52 sig_type=std_logic lab=adc_clk}
C {devices/lab_wire.sym} 2450 -740 0 1 {name=l53 sig_type=std_logic lab=comp_outm}
C {/home/users/nhpoole/ee272b/ee272b_mixed_signal_mmwave_accelerator/designs/latched_comparator_folded.sym} 2380 -720 2 1 {name=x1}
C {/home/users/nhpoole/ee272b/ee272b_mixed_signal_mmwave_accelerator/designs/se_fold_casc_wide_swing_opamp.sym} 2160 -750 0 0 {name=x53}
C {devices/lab_wire.sym} 2310 -750 0 0 {name=l54 sig_type=std_logic lab=vcom_buf}
